VERSION 5.7 ;
  NOWIREEXTENSIONATPIN ON ;
  DIVIDERCHAR "/" ;
  BUSBITCHARS "[]" ;
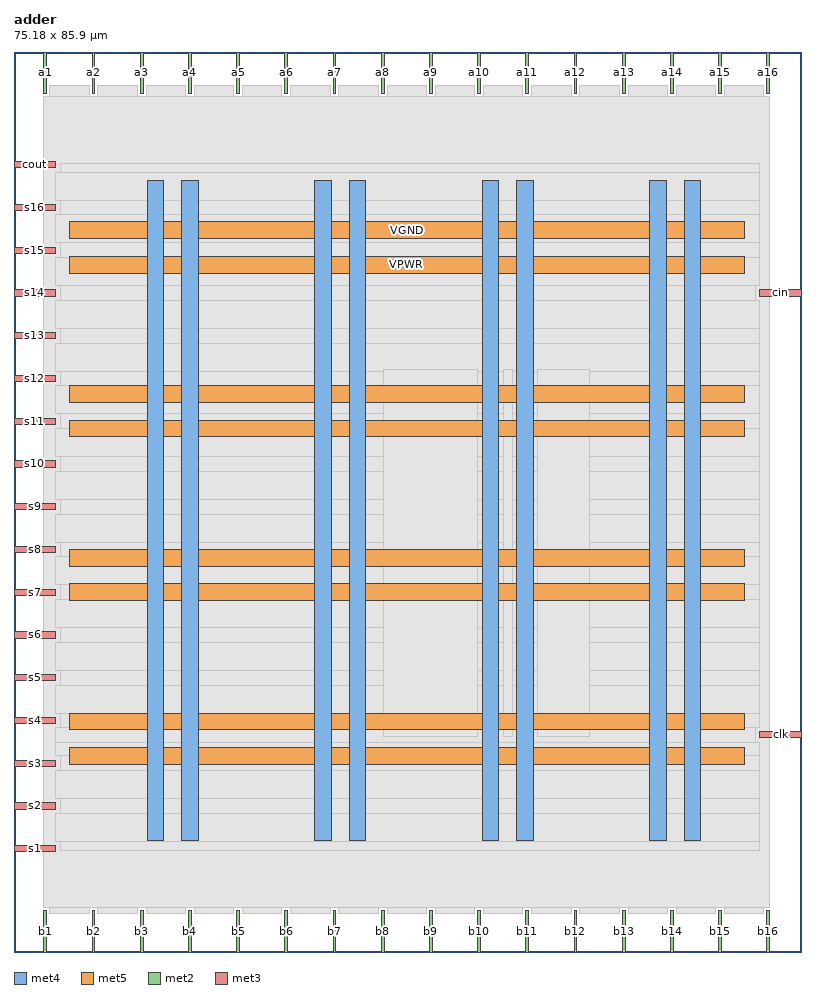
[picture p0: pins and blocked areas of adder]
MACRO adder
  CLASS BLOCK ;
  FOREIGN adder ;
  ORIGIN 0.000 0.000 ;
  SIZE 75.180 BY 85.900 ;
  PIN VGND
    DIRECTION INOUT ;
    USE GROUND ;
    PORT
      LAYER met4 ;
        RECT 16.010 10.640 17.610 73.680 ;
    END
    PORT
      LAYER met4 ;
        RECT 31.995 10.640 33.595 73.680 ;
    END
    PORT
      LAYER met4 ;
        RECT 47.980 10.640 49.580 73.680 ;
    END
    PORT
      LAYER met4 ;
        RECT 63.965 10.640 65.565 73.680 ;
    END
    PORT
      LAYER met5 ;
        RECT 5.280 21.195 69.700 22.795 ;
    END
    PORT
      LAYER met5 ;
        RECT 5.280 36.830 69.700 38.430 ;
    END
    PORT
      LAYER met5 ;
        RECT 5.280 52.465 69.700 54.065 ;
    END
    PORT
      LAYER met5 ;
        RECT 5.280 68.100 69.700 69.700 ;
    END
  END VGND
  PIN VPWR
    DIRECTION INOUT ;
    USE POWER ;
    PORT
      LAYER met4 ;
        RECT 12.710 10.640 14.310 73.680 ;
    END
    PORT
      LAYER met4 ;
        RECT 28.695 10.640 30.295 73.680 ;
    END
    PORT
      LAYER met4 ;
        RECT 44.680 10.640 46.280 73.680 ;
    END
    PORT
      LAYER met4 ;
        RECT 60.665 10.640 62.265 73.680 ;
    END
    PORT
      LAYER met5 ;
        RECT 5.280 17.895 69.700 19.495 ;
    END
    PORT
      LAYER met5 ;
        RECT 5.280 33.530 69.700 35.130 ;
    END
    PORT
      LAYER met5 ;
        RECT 5.280 49.165 69.700 50.765 ;
    END
    PORT
      LAYER met5 ;
        RECT 5.280 64.800 69.700 66.400 ;
    END
  END VPWR
  PIN a1
    DIRECTION INPUT ;
    USE SIGNAL ;
    ANTENNAGATEAREA 0.196500 ;
    PORT
      LAYER met2 ;
        RECT 2.850 81.900 3.130 85.900 ;
    END
  END a1
  PIN a10
    DIRECTION INPUT ;
    USE SIGNAL ;
    ANTENNAGATEAREA 0.196500 ;
    PORT
      LAYER met2 ;
        RECT 44.250 81.900 44.530 85.900 ;
    END
  END a10
  PIN a11
    DIRECTION INPUT ;
    USE SIGNAL ;
    ANTENNAGATEAREA 0.196500 ;
    PORT
      LAYER met2 ;
        RECT 48.850 81.900 49.130 85.900 ;
    END
  END a11
  PIN a12
    DIRECTION INPUT ;
    USE SIGNAL ;
    ANTENNAGATEAREA 0.196500 ;
    PORT
      LAYER met2 ;
        RECT 53.450 81.900 53.730 85.900 ;
    END
  END a12
  PIN a13
    DIRECTION INPUT ;
    USE SIGNAL ;
    ANTENNAGATEAREA 0.196500 ;
    PORT
      LAYER met2 ;
        RECT 58.050 81.900 58.330 85.900 ;
    END
  END a13
  PIN a14
    DIRECTION INPUT ;
    USE SIGNAL ;
    ANTENNAGATEAREA 0.196500 ;
    PORT
      LAYER met2 ;
        RECT 62.650 81.900 62.930 85.900 ;
    END
  END a14
  PIN a15
    DIRECTION INPUT ;
    USE SIGNAL ;
    ANTENNAGATEAREA 0.196500 ;
    PORT
      LAYER met2 ;
        RECT 67.250 81.900 67.530 85.900 ;
    END
  END a15
  PIN a16
    DIRECTION INPUT ;
    USE SIGNAL ;
    ANTENNAGATEAREA 0.196500 ;
    PORT
      LAYER met2 ;
        RECT 71.850 81.900 72.130 85.900 ;
    END
  END a16
  PIN a2
    DIRECTION INPUT ;
    USE SIGNAL ;
    ANTENNAGATEAREA 0.196500 ;
    PORT
      LAYER met2 ;
        RECT 7.450 81.900 7.730 85.900 ;
    END
  END a2
  PIN a3
    DIRECTION INPUT ;
    USE SIGNAL ;
    ANTENNAGATEAREA 0.196500 ;
    PORT
      LAYER met2 ;
        RECT 12.050 81.900 12.330 85.900 ;
    END
  END a3
  PIN a4
    DIRECTION INPUT ;
    USE SIGNAL ;
    ANTENNAGATEAREA 0.196500 ;
    PORT
      LAYER met2 ;
        RECT 16.650 81.900 16.930 85.900 ;
    END
  END a4
  PIN a5
    DIRECTION INPUT ;
    USE SIGNAL ;
    ANTENNAGATEAREA 0.196500 ;
    PORT
      LAYER met2 ;
        RECT 21.250 81.900 21.530 85.900 ;
    END
  END a5
  PIN a6
    DIRECTION INPUT ;
    USE SIGNAL ;
    ANTENNAGATEAREA 0.196500 ;
    PORT
      LAYER met2 ;
        RECT 25.850 81.900 26.130 85.900 ;
    END
  END a6
  PIN a7
    DIRECTION INPUT ;
    USE SIGNAL ;
    ANTENNAGATEAREA 0.196500 ;
    PORT
      LAYER met2 ;
        RECT 30.450 81.900 30.730 85.900 ;
    END
  END a7
  PIN a8
    DIRECTION INPUT ;
    USE SIGNAL ;
    ANTENNAGATEAREA 0.196500 ;
    PORT
      LAYER met2 ;
        RECT 35.050 81.900 35.330 85.900 ;
    END
  END a8
  PIN a9
    DIRECTION INPUT ;
    USE SIGNAL ;
    ANTENNAGATEAREA 0.196500 ;
    PORT
      LAYER met2 ;
        RECT 39.650 81.900 39.930 85.900 ;
    END
  END a9
  PIN b1
    DIRECTION INPUT ;
    USE SIGNAL ;
    ANTENNAGATEAREA 0.196500 ;
    PORT
      LAYER met2 ;
        RECT 2.850 0.000 3.130 4.000 ;
    END
  END b1
  PIN b10
    DIRECTION INPUT ;
    USE SIGNAL ;
    ANTENNAGATEAREA 0.196500 ;
    PORT
      LAYER met2 ;
        RECT 44.250 0.000 44.530 4.000 ;
    END
  END b10
  PIN b11
    DIRECTION INPUT ;
    USE SIGNAL ;
    ANTENNAGATEAREA 0.196500 ;
    PORT
      LAYER met2 ;
        RECT 48.850 0.000 49.130 4.000 ;
    END
  END b11
  PIN b12
    DIRECTION INPUT ;
    USE SIGNAL ;
    ANTENNAGATEAREA 0.196500 ;
    PORT
      LAYER met2 ;
        RECT 53.450 0.000 53.730 4.000 ;
    END
  END b12
  PIN b13
    DIRECTION INPUT ;
    USE SIGNAL ;
    ANTENNAGATEAREA 0.196500 ;
    PORT
      LAYER met2 ;
        RECT 58.050 0.000 58.330 4.000 ;
    END
  END b13
  PIN b14
    DIRECTION INPUT ;
    USE SIGNAL ;
    ANTENNAGATEAREA 0.196500 ;
    PORT
      LAYER met2 ;
        RECT 62.650 0.000 62.930 4.000 ;
    END
  END b14
  PIN b15
    DIRECTION INPUT ;
    USE SIGNAL ;
    ANTENNAGATEAREA 0.196500 ;
    PORT
      LAYER met2 ;
        RECT 67.250 0.000 67.530 4.000 ;
    END
  END b15
  PIN b16
    DIRECTION INPUT ;
    USE SIGNAL ;
    ANTENNAGATEAREA 0.196500 ;
    PORT
      LAYER met2 ;
        RECT 71.850 0.000 72.130 4.000 ;
    END
  END b16
  PIN b2
    DIRECTION INPUT ;
    USE SIGNAL ;
    ANTENNAGATEAREA 0.196500 ;
    PORT
      LAYER met2 ;
        RECT 7.450 0.000 7.730 4.000 ;
    END
  END b2
  PIN b3
    DIRECTION INPUT ;
    USE SIGNAL ;
    ANTENNAGATEAREA 0.196500 ;
    PORT
      LAYER met2 ;
        RECT 12.050 0.000 12.330 4.000 ;
    END
  END b3
  PIN b4
    DIRECTION INPUT ;
    USE SIGNAL ;
    ANTENNAGATEAREA 0.196500 ;
    PORT
      LAYER met2 ;
        RECT 16.650 0.000 16.930 4.000 ;
    END
  END b4
  PIN b5
    DIRECTION INPUT ;
    USE SIGNAL ;
    ANTENNAGATEAREA 0.196500 ;
    PORT
      LAYER met2 ;
        RECT 21.250 0.000 21.530 4.000 ;
    END
  END b5
  PIN b6
    DIRECTION INPUT ;
    USE SIGNAL ;
    ANTENNAGATEAREA 0.196500 ;
    PORT
      LAYER met2 ;
        RECT 25.850 0.000 26.130 4.000 ;
    END
  END b6
  PIN b7
    DIRECTION INPUT ;
    USE SIGNAL ;
    ANTENNAGATEAREA 0.196500 ;
    PORT
      LAYER met2 ;
        RECT 30.450 0.000 30.730 4.000 ;
    END
  END b7
  PIN b8
    DIRECTION INPUT ;
    USE SIGNAL ;
    ANTENNAGATEAREA 0.196500 ;
    PORT
      LAYER met2 ;
        RECT 35.050 0.000 35.330 4.000 ;
    END
  END b8
  PIN b9
    DIRECTION INPUT ;
    USE SIGNAL ;
    ANTENNAGATEAREA 0.196500 ;
    PORT
      LAYER met2 ;
        RECT 39.650 0.000 39.930 4.000 ;
    END
  END b9
  PIN cin
    DIRECTION INPUT ;
    USE SIGNAL ;
    ANTENNAGATEAREA 0.196500 ;
    PORT
      LAYER met3 ;
        RECT 71.180 62.600 75.180 63.200 ;
    END
  END cin
  PIN clk
    DIRECTION INPUT ;
    USE SIGNAL ;
    ANTENNAGATEAREA 0.852000 ;
    PORT
      LAYER met3 ;
        RECT 71.180 20.440 75.180 21.040 ;
    END
  END clk
  PIN cout
    DIRECTION OUTPUT ;
    USE SIGNAL ;
    ANTENNADIFFAREA 0.340600 ;
    PORT
      LAYER met3 ;
        RECT 0.000 74.840 4.000 75.440 ;
    END
  END cout
  PIN s1
    DIRECTION OUTPUT ;
    USE SIGNAL ;
    ANTENNADIFFAREA 0.340600 ;
    PORT
      LAYER met3 ;
        RECT 0.000 9.560 4.000 10.160 ;
    END
  END s1
  PIN s10
    DIRECTION OUTPUT ;
    USE SIGNAL ;
    ANTENNADIFFAREA 0.340600 ;
    PORT
      LAYER met3 ;
        RECT 0.000 46.280 4.000 46.880 ;
    END
  END s10
  PIN s11
    DIRECTION OUTPUT ;
    USE SIGNAL ;
    ANTENNADIFFAREA 0.340600 ;
    PORT
      LAYER met3 ;
        RECT 0.000 50.360 4.000 50.960 ;
    END
  END s11
  PIN s12
    DIRECTION OUTPUT ;
    USE SIGNAL ;
    ANTENNADIFFAREA 0.340600 ;
    PORT
      LAYER met3 ;
        RECT 0.000 54.440 4.000 55.040 ;
    END
  END s12
  PIN s13
    DIRECTION OUTPUT ;
    USE SIGNAL ;
    ANTENNADIFFAREA 0.340600 ;
    PORT
      LAYER met3 ;
        RECT 0.000 58.520 4.000 59.120 ;
    END
  END s13
  PIN s14
    DIRECTION OUTPUT ;
    USE SIGNAL ;
    ANTENNADIFFAREA 0.340600 ;
    PORT
      LAYER met3 ;
        RECT 0.000 62.600 4.000 63.200 ;
    END
  END s14
  PIN s15
    DIRECTION OUTPUT ;
    USE SIGNAL ;
    ANTENNADIFFAREA 0.340600 ;
    PORT
      LAYER met3 ;
        RECT 0.000 66.680 4.000 67.280 ;
    END
  END s15
  PIN s16
    DIRECTION OUTPUT ;
    USE SIGNAL ;
    ANTENNADIFFAREA 0.340600 ;
    PORT
      LAYER met3 ;
        RECT 0.000 70.760 4.000 71.360 ;
    END
  END s16
  PIN s2
    DIRECTION OUTPUT ;
    USE SIGNAL ;
    ANTENNADIFFAREA 0.340600 ;
    PORT
      LAYER met3 ;
        RECT 0.000 13.640 4.000 14.240 ;
    END
  END s2
  PIN s3
    DIRECTION OUTPUT ;
    USE SIGNAL ;
    ANTENNADIFFAREA 0.340600 ;
    PORT
      LAYER met3 ;
        RECT 0.000 17.720 4.000 18.320 ;
    END
  END s3
  PIN s4
    DIRECTION OUTPUT ;
    USE SIGNAL ;
    ANTENNADIFFAREA 0.340600 ;
    PORT
      LAYER met3 ;
        RECT 0.000 21.800 4.000 22.400 ;
    END
  END s4
  PIN s5
    DIRECTION OUTPUT ;
    USE SIGNAL ;
    ANTENNADIFFAREA 0.340600 ;
    PORT
      LAYER met3 ;
        RECT 0.000 25.880 4.000 26.480 ;
    END
  END s5
  PIN s6
    DIRECTION OUTPUT ;
    USE SIGNAL ;
    ANTENNADIFFAREA 0.340600 ;
    PORT
      LAYER met3 ;
        RECT 0.000 29.960 4.000 30.560 ;
    END
  END s6
  PIN s7
    DIRECTION OUTPUT ;
    USE SIGNAL ;
    ANTENNADIFFAREA 0.340600 ;
    PORT
      LAYER met3 ;
        RECT 0.000 34.040 4.000 34.640 ;
    END
  END s7
  PIN s8
    DIRECTION OUTPUT ;
    USE SIGNAL ;
    ANTENNADIFFAREA 0.340600 ;
    PORT
      LAYER met3 ;
        RECT 0.000 38.120 4.000 38.720 ;
    END
  END s8
  PIN s9
    DIRECTION OUTPUT ;
    USE SIGNAL ;
    ANTENNADIFFAREA 0.340600 ;
    PORT
      LAYER met3 ;
        RECT 0.000 42.200 4.000 42.800 ;
    END
  END s9
  OBS
      LAYER nwell ;
        RECT 5.330 10.795 69.650 73.630 ;
      LAYER li1 ;
        RECT 5.520 10.795 69.460 73.525 ;
      LAYER met1 ;
        RECT 2.830 10.640 72.150 73.680 ;
      LAYER met2 ;
        RECT 3.410 81.620 7.170 82.690 ;
        RECT 8.010 81.620 11.770 82.690 ;
        RECT 12.610 81.620 16.370 82.690 ;
        RECT 17.210 81.620 20.970 82.690 ;
        RECT 21.810 81.620 25.570 82.690 ;
        RECT 26.410 81.620 30.170 82.690 ;
        RECT 31.010 81.620 34.770 82.690 ;
        RECT 35.610 81.620 39.370 82.690 ;
        RECT 40.210 81.620 43.970 82.690 ;
        RECT 44.810 81.620 48.570 82.690 ;
        RECT 49.410 81.620 53.170 82.690 ;
        RECT 54.010 81.620 57.770 82.690 ;
        RECT 58.610 81.620 62.370 82.690 ;
        RECT 63.210 81.620 66.970 82.690 ;
        RECT 67.810 81.620 71.570 82.690 ;
        RECT 2.860 4.280 72.120 81.620 ;
        RECT 3.410 3.670 7.170 4.280 ;
        RECT 8.010 3.670 11.770 4.280 ;
        RECT 12.610 3.670 16.370 4.280 ;
        RECT 17.210 3.670 20.970 4.280 ;
        RECT 21.810 3.670 25.570 4.280 ;
        RECT 26.410 3.670 30.170 4.280 ;
        RECT 31.010 3.670 34.770 4.280 ;
        RECT 35.610 3.670 39.370 4.280 ;
        RECT 40.210 3.670 43.970 4.280 ;
        RECT 44.810 3.670 48.570 4.280 ;
        RECT 49.410 3.670 53.170 4.280 ;
        RECT 54.010 3.670 57.770 4.280 ;
        RECT 58.610 3.670 62.370 4.280 ;
        RECT 63.210 3.670 66.970 4.280 ;
        RECT 67.810 3.670 71.570 4.280 ;
      LAYER met3 ;
        RECT 4.400 74.440 71.180 75.305 ;
        RECT 3.990 71.760 71.180 74.440 ;
        RECT 4.400 70.360 71.180 71.760 ;
        RECT 3.990 67.680 71.180 70.360 ;
        RECT 4.400 66.280 71.180 67.680 ;
        RECT 3.990 63.600 71.180 66.280 ;
        RECT 4.400 62.200 70.780 63.600 ;
        RECT 3.990 59.520 71.180 62.200 ;
        RECT 4.400 58.120 71.180 59.520 ;
        RECT 3.990 55.440 71.180 58.120 ;
        RECT 4.400 54.040 71.180 55.440 ;
        RECT 3.990 51.360 71.180 54.040 ;
        RECT 4.400 49.960 71.180 51.360 ;
        RECT 3.990 47.280 71.180 49.960 ;
        RECT 4.400 45.880 71.180 47.280 ;
        RECT 3.990 43.200 71.180 45.880 ;
        RECT 4.400 41.800 71.180 43.200 ;
        RECT 3.990 39.120 71.180 41.800 ;
        RECT 4.400 37.720 71.180 39.120 ;
        RECT 3.990 35.040 71.180 37.720 ;
        RECT 4.400 33.640 71.180 35.040 ;
        RECT 3.990 30.960 71.180 33.640 ;
        RECT 4.400 29.560 71.180 30.960 ;
        RECT 3.990 26.880 71.180 29.560 ;
        RECT 4.400 25.480 71.180 26.880 ;
        RECT 3.990 22.800 71.180 25.480 ;
        RECT 4.400 21.440 71.180 22.800 ;
        RECT 4.400 21.400 70.780 21.440 ;
        RECT 3.990 20.040 70.780 21.400 ;
        RECT 3.990 18.720 71.180 20.040 ;
        RECT 4.400 17.320 71.180 18.720 ;
        RECT 3.990 14.640 71.180 17.320 ;
        RECT 4.400 13.240 71.180 14.640 ;
        RECT 3.990 10.560 71.180 13.240 ;
        RECT 4.400 9.695 71.180 10.560 ;
      LAYER met4 ;
        RECT 35.255 20.575 44.280 55.585 ;
        RECT 46.680 20.575 47.580 55.585 ;
        RECT 49.980 20.575 54.905 55.585 ;
  END
END adder
END LIBRARY

